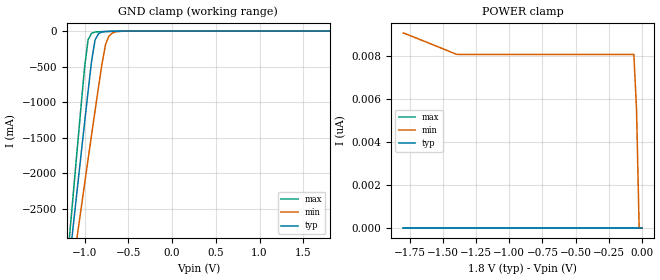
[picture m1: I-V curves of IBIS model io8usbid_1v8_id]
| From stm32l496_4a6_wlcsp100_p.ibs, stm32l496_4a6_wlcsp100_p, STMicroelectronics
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|   Model io8usbid_1v8_id
[Model]  io8usbid_1v8_id
Model_type Input
Polarity   Non-Inverting
Vinl =   0.540000V
Vinh =   1.260000V
C_comp   2.031500pF   1.968500pF   2.084900pF
[Temperature Range]   25.000000   0.125000k   -40.000000
[Pullup Reference]   1.800000V   1.600000V   2.000000V
[Pulldown Reference]   0.0V   0.0V   0.0V
[POWER Clamp Reference]   1.800000V   1.600000V   2.000000V
[GND Clamp Reference]   0.0V   0.0V   0.0V
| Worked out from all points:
|   GND clamp passes 1 mA (typ) near -0.60 V on its own axis
[GND_clamp]
|Voltage   I(typ)   I(min)   I(max)
-1.8V     -9.895A    -9.296A    -9.457A
-1.2V     -3.533A    -3.902A    -3.274A
-1.16V    -3.082A    -3.55A     -2.716A
-1.12V    -2.631A    -3.198A    -2.159A
-1.08V    -2.182A    -2.848A    -1.604A
-1V       -1.289A    -2.15A     -512mA
-960mV    -849.4mA   -1.803A    -123.8mA
-920mV    -422.4mA   -1.459A    -30.79mA
-880mV    -123.7mA   -1.118A    -13.63mA
-760mV    -6.32mA    -185mA     -5.692mA
-680mV    -2.569mA   -25.43mA   -2.907mA
1.8V      0A         0A         0A
[POWER_clamp]
|Voltage   I(typ)   I(min)   I(max)
-1.8V     0A         9.088nA    0A
-1.4V     0A         8.095nA    0A
-60mV     0A         8.085nA    0A
-40mV     0A         5.539nA    0A
-20mV     0A         0A         0A
0V        0A         0A         0A
